VERSION 5.7 ;
  NOWIREEXTENSIONATPIN ON ;
  DIVIDERCHAR "/" ;
  BUSBITCHARS "[]" ;
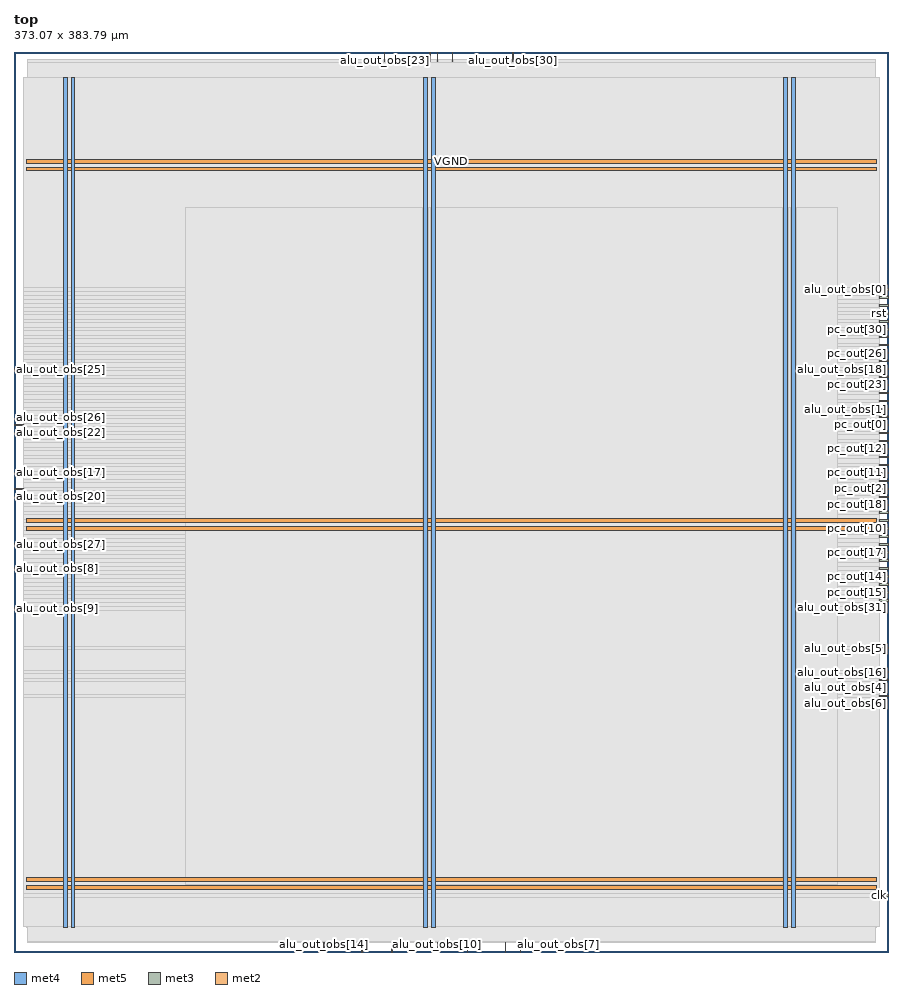
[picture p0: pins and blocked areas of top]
MACRO top
  CLASS BLOCK ;
  FOREIGN top ;
  ORIGIN 0.000 0.000 ;
  SIZE 373.070 BY 383.790 ;
  PIN VGND
    DIRECTION INOUT ;
    USE GROUND ;
    PORT
      LAYER met4 ;
        RECT 24.340 10.640 25.940 372.880 ;
    END
    PORT
      LAYER met4 ;
        RECT 177.940 10.640 179.540 372.880 ;
    END
    PORT
      LAYER met4 ;
        RECT 331.540 10.640 333.140 372.880 ;
    END
    PORT
      LAYER met5 ;
        RECT 5.280 30.030 367.780 31.630 ;
    END
    PORT
      LAYER met5 ;
        RECT 5.280 183.210 367.780 184.810 ;
    END
    PORT
      LAYER met5 ;
        RECT 5.280 336.390 367.780 337.990 ;
    END
  END VGND
  PIN VPWR
    DIRECTION INOUT ;
    USE POWER ;
    PORT
      LAYER met4 ;
        RECT 21.040 10.640 22.640 372.880 ;
    END
    PORT
      LAYER met4 ;
        RECT 174.640 10.640 176.240 372.880 ;
    END
    PORT
      LAYER met4 ;
        RECT 328.240 10.640 329.840 372.880 ;
    END
    PORT
      LAYER met5 ;
        RECT 5.280 26.730 367.780 28.330 ;
    END
    PORT
      LAYER met5 ;
        RECT 5.280 179.910 367.780 181.510 ;
    END
    PORT
      LAYER met5 ;
        RECT 5.280 333.090 367.780 334.690 ;
    END
  END VPWR
  PIN alu_out_obs[0]
    DIRECTION OUTPUT ;
    USE SIGNAL ;
    ANTENNAGATEAREA 0.434700 ;
    ANTENNADIFFAREA 0.775300 ;
    PORT
      LAYER met3 ;
        RECT 369.070 282.240 373.070 282.840 ;
    END
  END alu_out_obs[0]
  PIN alu_out_obs[10]
    DIRECTION OUTPUT ;
    USE SIGNAL ;
    ANTENNAGATEAREA 0.434700 ;
    ANTENNADIFFAREA 0.775300 ;
    PORT
      LAYER met2 ;
        RECT 180.410 0.000 180.690 4.000 ;
    END
  END alu_out_obs[10]
  PIN alu_out_obs[11]
    DIRECTION OUTPUT ;
    USE SIGNAL ;
    ANTENNAGATEAREA 0.434700 ;
    ANTENNADIFFAREA 0.775300 ;
    PORT
      LAYER met2 ;
        RECT 161.090 0.000 161.370 4.000 ;
    END
  END alu_out_obs[11]
  PIN alu_out_obs[12]
    DIRECTION OUTPUT ;
    USE SIGNAL ;
    ANTENNAGATEAREA 0.434700 ;
    ANTENNADIFFAREA 0.775300 ;
    PORT
      LAYER met2 ;
        RECT 177.190 379.790 177.470 383.790 ;
    END
  END alu_out_obs[12]
  PIN alu_out_obs[13]
    DIRECTION OUTPUT ;
    USE SIGNAL ;
    ANTENNAGATEAREA 0.434700 ;
    ANTENNADIFFAREA 0.775300 ;
    PORT
      LAYER met2 ;
        RECT 186.850 379.790 187.130 383.790 ;
    END
  END alu_out_obs[13]
  PIN alu_out_obs[14]
    DIRECTION OUTPUT ;
    USE SIGNAL ;
    ANTENNAGATEAREA 0.434700 ;
    ANTENNADIFFAREA 0.775300 ;
    PORT
      LAYER met2 ;
        RECT 132.110 0.000 132.390 4.000 ;
    END
  END alu_out_obs[14]
  PIN alu_out_obs[15]
    DIRECTION OUTPUT ;
    USE SIGNAL ;
    ANTENNAGATEAREA 0.434700 ;
    ANTENNADIFFAREA 0.775300 ;
    PORT
      LAYER met2 ;
        RECT 215.830 0.000 216.110 4.000 ;
    END
  END alu_out_obs[15]
  PIN alu_out_obs[16]
    DIRECTION OUTPUT ;
    USE SIGNAL ;
    ANTENNAGATEAREA 0.434700 ;
    ANTENNADIFFAREA 0.775300 ;
    PORT
      LAYER met3 ;
        RECT 369.070 119.040 373.070 119.640 ;
    END
  END alu_out_obs[16]
  PIN alu_out_obs[17]
    DIRECTION OUTPUT ;
    USE SIGNAL ;
    ANTENNAGATEAREA 0.434700 ;
    ANTENNADIFFAREA 0.775300 ;
    PORT
      LAYER met3 ;
        RECT 0.000 204.040 4.000 204.640 ;
    END
  END alu_out_obs[17]
  PIN alu_out_obs[18]
    DIRECTION OUTPUT ;
    USE SIGNAL ;
    ANTENNAGATEAREA 0.434700 ;
    ANTENNADIFFAREA 0.775300 ;
    PORT
      LAYER met3 ;
        RECT 369.070 248.240 373.070 248.840 ;
    END
  END alu_out_obs[18]
  PIN alu_out_obs[19]
    DIRECTION OUTPUT ;
    USE SIGNAL ;
    ANTENNAGATEAREA 0.434700 ;
    ANTENNADIFFAREA 0.775300 ;
    PORT
      LAYER met2 ;
        RECT 180.410 379.790 180.690 383.790 ;
    END
  END alu_out_obs[19]
  PIN alu_out_obs[1]
    DIRECTION OUTPUT ;
    USE SIGNAL ;
    ANTENNAGATEAREA 0.434700 ;
    ANTENNADIFFAREA 0.775300 ;
    PORT
      LAYER met3 ;
        RECT 369.070 231.240 373.070 231.840 ;
    END
  END alu_out_obs[1]
  PIN alu_out_obs[20]
    DIRECTION OUTPUT ;
    USE SIGNAL ;
    ANTENNAGATEAREA 0.434700 ;
    ANTENNADIFFAREA 0.775300 ;
    PORT
      LAYER met3 ;
        RECT 0.000 193.840 4.000 194.440 ;
    END
  END alu_out_obs[20]
  PIN alu_out_obs[21]
    DIRECTION OUTPUT ;
    USE SIGNAL ;
    ANTENNAGATEAREA 0.434700 ;
    ANTENNADIFFAREA 0.775300 ;
    PORT
      LAYER met3 ;
        RECT 0.000 197.240 4.000 197.840 ;
    END
  END alu_out_obs[21]
  PIN alu_out_obs[22]
    DIRECTION OUTPUT ;
    USE SIGNAL ;
    ANTENNAGATEAREA 0.434700 ;
    ANTENNADIFFAREA 0.775300 ;
    PORT
      LAYER met3 ;
        RECT 0.000 221.040 4.000 221.640 ;
    END
  END alu_out_obs[22]
  PIN alu_out_obs[23]
    DIRECTION OUTPUT ;
    USE SIGNAL ;
    ANTENNAGATEAREA 0.434700 ;
    ANTENNADIFFAREA 0.775300 ;
    PORT
      LAYER met2 ;
        RECT 157.870 379.790 158.150 383.790 ;
    END
  END alu_out_obs[23]
  PIN alu_out_obs[24]
    DIRECTION OUTPUT ;
    USE SIGNAL ;
    ANTENNAGATEAREA 0.434700 ;
    ANTENNADIFFAREA 0.775300 ;
    PORT
      LAYER met2 ;
        RECT 193.290 0.000 193.570 4.000 ;
    END
  END alu_out_obs[24]
  PIN alu_out_obs[25]
    DIRECTION OUTPUT ;
    USE SIGNAL ;
    ANTENNAGATEAREA 0.434700 ;
    ANTENNADIFFAREA 0.775300 ;
    PORT
      LAYER met3 ;
        RECT 0.000 248.240 4.000 248.840 ;
    END
  END alu_out_obs[25]
  PIN alu_out_obs[26]
    DIRECTION OUTPUT ;
    USE SIGNAL ;
    ANTENNAGATEAREA 0.434700 ;
    ANTENNADIFFAREA 0.775300 ;
    PORT
      LAYER met3 ;
        RECT 0.000 224.440 4.000 225.040 ;
    END
  END alu_out_obs[26]
  PIN alu_out_obs[27]
    DIRECTION OUTPUT ;
    USE SIGNAL ;
    ANTENNAGATEAREA 0.434700 ;
    ANTENNADIFFAREA 0.775300 ;
    PORT
      LAYER met3 ;
        RECT 0.000 173.440 4.000 174.040 ;
    END
  END alu_out_obs[27]
  PIN alu_out_obs[28]
    DIRECTION OUTPUT ;
    USE SIGNAL ;
    ANTENNAGATEAREA 0.434700 ;
    ANTENNADIFFAREA 0.775300 ;
    PORT
      LAYER met2 ;
        RECT 148.210 0.000 148.490 4.000 ;
    END
  END alu_out_obs[28]
  PIN alu_out_obs[29]
    DIRECTION OUTPUT ;
    USE SIGNAL ;
    ANTENNAGATEAREA 0.434700 ;
    ANTENNADIFFAREA 0.775300 ;
    PORT
      LAYER met2 ;
        RECT 209.390 0.000 209.670 4.000 ;
    END
  END alu_out_obs[29]
  PIN alu_out_obs[2]
    DIRECTION OUTPUT ;
    USE SIGNAL ;
    ANTENNAGATEAREA 0.434700 ;
    ANTENNADIFFAREA 0.775300 ;
    PORT
      LAYER met3 ;
        RECT 369.070 251.640 373.070 252.240 ;
    END
  END alu_out_obs[2]
  PIN alu_out_obs[30]
    DIRECTION OUTPUT ;
    USE SIGNAL ;
    ANTENNAGATEAREA 0.434700 ;
    ANTENNADIFFAREA 0.775300 ;
    PORT
      LAYER met2 ;
        RECT 212.610 379.790 212.890 383.790 ;
    END
  END alu_out_obs[30]
  PIN alu_out_obs[31]
    DIRECTION OUTPUT ;
    USE SIGNAL ;
    ANTENNAGATEAREA 0.434700 ;
    ANTENNADIFFAREA 0.775300 ;
    PORT
      LAYER met3 ;
        RECT 369.070 149.640 373.070 150.240 ;
    END
  END alu_out_obs[31]
  PIN alu_out_obs[3]
    DIRECTION OUTPUT ;
    USE SIGNAL ;
    ANTENNAGATEAREA 0.434700 ;
    ANTENNADIFFAREA 0.775300 ;
    PORT
      LAYER met3 ;
        RECT 369.070 258.440 373.070 259.040 ;
    END
  END alu_out_obs[3]
  PIN alu_out_obs[4]
    DIRECTION OUTPUT ;
    USE SIGNAL ;
    ANTENNAGATEAREA 0.434700 ;
    ANTENNADIFFAREA 0.775300 ;
    PORT
      LAYER met3 ;
        RECT 369.070 115.640 373.070 116.240 ;
    END
  END alu_out_obs[4]
  PIN alu_out_obs[5]
    DIRECTION OUTPUT ;
    USE SIGNAL ;
    ANTENNAGATEAREA 0.434700 ;
    ANTENNADIFFAREA 0.775300 ;
    PORT
      LAYER met3 ;
        RECT 369.070 129.240 373.070 129.840 ;
    END
  END alu_out_obs[5]
  PIN alu_out_obs[6]
    DIRECTION OUTPUT ;
    USE SIGNAL ;
    ANTENNAGATEAREA 0.434700 ;
    ANTENNADIFFAREA 0.775300 ;
    PORT
      LAYER met3 ;
        RECT 369.070 108.840 373.070 109.440 ;
    END
  END alu_out_obs[6]
  PIN alu_out_obs[7]
    DIRECTION OUTPUT ;
    USE SIGNAL ;
    ANTENNAGATEAREA 0.434700 ;
    ANTENNADIFFAREA 0.775300 ;
    PORT
      LAYER met2 ;
        RECT 231.930 0.000 232.210 4.000 ;
    END
  END alu_out_obs[7]
  PIN alu_out_obs[8]
    DIRECTION OUTPUT ;
    USE SIGNAL ;
    ANTENNAGATEAREA 0.434700 ;
    ANTENNADIFFAREA 0.775300 ;
    PORT
      LAYER met3 ;
        RECT 0.000 163.240 4.000 163.840 ;
    END
  END alu_out_obs[8]
  PIN alu_out_obs[9]
    DIRECTION OUTPUT ;
    USE SIGNAL ;
    ANTENNAGATEAREA 0.434700 ;
    ANTENNADIFFAREA 0.775300 ;
    PORT
      LAYER met3 ;
        RECT 0.000 146.240 4.000 146.840 ;
    END
  END alu_out_obs[9]
  PIN clk
    DIRECTION INPUT ;
    USE SIGNAL ;
    ANTENNAGATEAREA 1.286700 ;
    ANTENNADIFFAREA 0.434700 ;
    PORT
      LAYER met3 ;
        RECT 369.070 23.840 373.070 24.440 ;
    END
  END clk
  PIN pc_out[0]
    DIRECTION OUTPUT ;
    USE SIGNAL ;
    ANTENNAGATEAREA 0.434700 ;
    ANTENNADIFFAREA 0.775300 ;
    PORT
      LAYER met3 ;
        RECT 369.070 227.840 373.070 228.440 ;
    END
  END pc_out[0]
  PIN pc_out[10]
    DIRECTION OUTPUT ;
    USE SIGNAL ;
    ANTENNAGATEAREA 0.434700 ;
    ANTENNADIFFAREA 0.775300 ;
    PORT
      LAYER met3 ;
        RECT 369.070 180.240 373.070 180.840 ;
    END
  END pc_out[10]
  PIN pc_out[11]
    DIRECTION OUTPUT ;
    USE SIGNAL ;
    ANTENNAGATEAREA 0.434700 ;
    ANTENNADIFFAREA 0.775300 ;
    PORT
      LAYER met3 ;
        RECT 369.070 204.040 373.070 204.640 ;
    END
  END pc_out[11]
  PIN pc_out[12]
    DIRECTION OUTPUT ;
    USE SIGNAL ;
    ANTENNAGATEAREA 0.434700 ;
    ANTENNADIFFAREA 0.775300 ;
    PORT
      LAYER met3 ;
        RECT 369.070 214.240 373.070 214.840 ;
    END
  END pc_out[12]
  PIN pc_out[13]
    DIRECTION OUTPUT ;
    USE SIGNAL ;
    ANTENNAGATEAREA 0.434700 ;
    ANTENNADIFFAREA 0.775300 ;
    PORT
      LAYER met3 ;
        RECT 369.070 210.840 373.070 211.440 ;
    END
  END pc_out[13]
  PIN pc_out[14]
    DIRECTION OUTPUT ;
    USE SIGNAL ;
    ANTENNAGATEAREA 0.434700 ;
    ANTENNADIFFAREA 0.775300 ;
    PORT
      LAYER met3 ;
        RECT 369.070 159.840 373.070 160.440 ;
    END
  END pc_out[14]
  PIN pc_out[15]
    DIRECTION OUTPUT ;
    USE SIGNAL ;
    ANTENNAGATEAREA 0.434700 ;
    ANTENNADIFFAREA 0.775300 ;
    PORT
      LAYER met3 ;
        RECT 369.070 153.040 373.070 153.640 ;
    END
  END pc_out[15]
  PIN pc_out[16]
    DIRECTION OUTPUT ;
    USE SIGNAL ;
    ANTENNAGATEAREA 0.434700 ;
    ANTENNADIFFAREA 0.775300 ;
    PORT
      LAYER met3 ;
        RECT 369.070 207.440 373.070 208.040 ;
    END
  END pc_out[16]
  PIN pc_out[17]
    DIRECTION OUTPUT ;
    USE SIGNAL ;
    ANTENNAGATEAREA 0.434700 ;
    ANTENNADIFFAREA 0.775300 ;
    PORT
      LAYER met3 ;
        RECT 369.070 170.040 373.070 170.640 ;
    END
  END pc_out[17]
  PIN pc_out[18]
    DIRECTION OUTPUT ;
    USE SIGNAL ;
    ANTENNAGATEAREA 0.434700 ;
    ANTENNADIFFAREA 0.775300 ;
    PORT
      LAYER met3 ;
        RECT 369.070 190.440 373.070 191.040 ;
    END
  END pc_out[18]
  PIN pc_out[19]
    DIRECTION OUTPUT ;
    USE SIGNAL ;
    ANTENNAGATEAREA 0.434700 ;
    ANTENNADIFFAREA 0.775300 ;
    PORT
      LAYER met3 ;
        RECT 369.070 200.640 373.070 201.240 ;
    END
  END pc_out[19]
  PIN pc_out[1]
    DIRECTION OUTPUT ;
    USE SIGNAL ;
    ANTENNAGATEAREA 0.434700 ;
    ANTENNADIFFAREA 0.775300 ;
    PORT
      LAYER met3 ;
        RECT 369.070 217.640 373.070 218.240 ;
    END
  END pc_out[1]
  PIN pc_out[20]
    DIRECTION OUTPUT ;
    USE SIGNAL ;
    ANTENNAGATEAREA 0.434700 ;
    ANTENNADIFFAREA 0.775300 ;
    PORT
      LAYER met3 ;
        RECT 369.070 224.440 373.070 225.040 ;
    END
  END pc_out[20]
  PIN pc_out[21]
    DIRECTION OUTPUT ;
    USE SIGNAL ;
    ANTENNAGATEAREA 0.434700 ;
    ANTENNADIFFAREA 0.775300 ;
    PORT
      LAYER met3 ;
        RECT 369.070 234.640 373.070 235.240 ;
    END
  END pc_out[21]
  PIN pc_out[22]
    DIRECTION OUTPUT ;
    USE SIGNAL ;
    ANTENNAGATEAREA 0.434700 ;
    ANTENNADIFFAREA 0.775300 ;
    PORT
      LAYER met3 ;
        RECT 369.070 221.040 373.070 221.640 ;
    END
  END pc_out[22]
  PIN pc_out[23]
    DIRECTION OUTPUT ;
    USE SIGNAL ;
    ANTENNAGATEAREA 0.434700 ;
    ANTENNADIFFAREA 0.775300 ;
    PORT
      LAYER met3 ;
        RECT 369.070 244.840 373.070 245.440 ;
    END
  END pc_out[23]
  PIN pc_out[24]
    DIRECTION OUTPUT ;
    USE SIGNAL ;
    ANTENNAGATEAREA 0.434700 ;
    ANTENNADIFFAREA 0.775300 ;
    PORT
      LAYER met3 ;
        RECT 369.070 238.040 373.070 238.640 ;
    END
  END pc_out[24]
  PIN pc_out[25]
    DIRECTION OUTPUT ;
    USE SIGNAL ;
    ANTENNAGATEAREA 0.434700 ;
    ANTENNADIFFAREA 0.775300 ;
    PORT
      LAYER met3 ;
        RECT 369.070 241.440 373.070 242.040 ;
    END
  END pc_out[25]
  PIN pc_out[26]
    DIRECTION OUTPUT ;
    USE SIGNAL ;
    ANTENNAGATEAREA 0.434700 ;
    ANTENNADIFFAREA 0.775300 ;
    PORT
      LAYER met3 ;
        RECT 369.070 255.040 373.070 255.640 ;
    END
  END pc_out[26]
  PIN pc_out[27]
    DIRECTION OUTPUT ;
    USE SIGNAL ;
    ANTENNAGATEAREA 0.434700 ;
    ANTENNADIFFAREA 0.775300 ;
    PORT
      LAYER met3 ;
        RECT 369.070 278.840 373.070 279.440 ;
    END
  END pc_out[27]
  PIN pc_out[28]
    DIRECTION OUTPUT ;
    USE SIGNAL ;
    ANTENNAGATEAREA 0.434700 ;
    ANTENNADIFFAREA 0.775300 ;
    PORT
      LAYER met3 ;
        RECT 369.070 261.840 373.070 262.440 ;
    END
  END pc_out[28]
  PIN pc_out[29]
    DIRECTION OUTPUT ;
    USE SIGNAL ;
    ANTENNAGATEAREA 0.434700 ;
    ANTENNADIFFAREA 0.775300 ;
    PORT
      LAYER met3 ;
        RECT 369.070 268.640 373.070 269.240 ;
    END
  END pc_out[29]
  PIN pc_out[2]
    DIRECTION OUTPUT ;
    USE SIGNAL ;
    ANTENNAGATEAREA 0.434700 ;
    ANTENNADIFFAREA 0.775300 ;
    PORT
      LAYER met3 ;
        RECT 369.070 197.240 373.070 197.840 ;
    END
  END pc_out[2]
  PIN pc_out[30]
    DIRECTION OUTPUT ;
    USE SIGNAL ;
    ANTENNAGATEAREA 0.434700 ;
    ANTENNADIFFAREA 0.775300 ;
    PORT
      LAYER met3 ;
        RECT 369.070 265.240 373.070 265.840 ;
    END
  END pc_out[30]
  PIN pc_out[31]
    DIRECTION OUTPUT ;
    USE SIGNAL ;
    ANTENNAGATEAREA 0.434700 ;
    ANTENNADIFFAREA 0.775300 ;
    PORT
      LAYER met3 ;
        RECT 369.070 275.440 373.070 276.040 ;
    END
  END pc_out[31]
  PIN pc_out[3]
    DIRECTION OUTPUT ;
    USE SIGNAL ;
    ANTENNAGATEAREA 0.434700 ;
    ANTENNADIFFAREA 0.775300 ;
    PORT
      LAYER met3 ;
        RECT 369.070 176.840 373.070 177.440 ;
    END
  END pc_out[3]
  PIN pc_out[4]
    DIRECTION OUTPUT ;
    USE SIGNAL ;
    ANTENNAGATEAREA 0.434700 ;
    ANTENNADIFFAREA 0.775300 ;
    PORT
      LAYER met3 ;
        RECT 369.070 183.640 373.070 184.240 ;
    END
  END pc_out[4]
  PIN pc_out[5]
    DIRECTION OUTPUT ;
    USE SIGNAL ;
    ANTENNAGATEAREA 0.434700 ;
    ANTENNADIFFAREA 0.775300 ;
    PORT
      LAYER met3 ;
        RECT 369.070 187.040 373.070 187.640 ;
    END
  END pc_out[5]
  PIN pc_out[6]
    DIRECTION OUTPUT ;
    USE SIGNAL ;
    ANTENNAGATEAREA 0.434700 ;
    ANTENNADIFFAREA 0.775300 ;
    PORT
      LAYER met3 ;
        RECT 369.070 173.440 373.070 174.040 ;
    END
  END pc_out[6]
  PIN pc_out[7]
    DIRECTION OUTPUT ;
    USE SIGNAL ;
    ANTENNAGATEAREA 0.434700 ;
    ANTENNADIFFAREA 0.775300 ;
    PORT
      LAYER met3 ;
        RECT 369.070 163.240 373.070 163.840 ;
    END
  END pc_out[7]
  PIN pc_out[8]
    DIRECTION OUTPUT ;
    USE SIGNAL ;
    ANTENNAGATEAREA 0.434700 ;
    ANTENNADIFFAREA 0.775300 ;
    PORT
      LAYER met3 ;
        RECT 369.070 166.640 373.070 167.240 ;
    END
  END pc_out[8]
  PIN pc_out[9]
    DIRECTION OUTPUT ;
    USE SIGNAL ;
    ANTENNAGATEAREA 0.434700 ;
    ANTENNADIFFAREA 0.775300 ;
    PORT
      LAYER met3 ;
        RECT 369.070 193.840 373.070 194.440 ;
    END
  END pc_out[9]
  PIN reg_write_obs
    DIRECTION OUTPUT ;
    USE SIGNAL ;
    ANTENNAGATEAREA 0.434700 ;
    ANTENNADIFFAREA 0.775300 ;
    PORT
      LAYER met3 ;
        RECT 369.070 156.440 373.070 157.040 ;
    END
  END reg_write_obs
  PIN rst
    DIRECTION INPUT ;
    USE SIGNAL ;
    ANTENNAGATEAREA 0.560700 ;
    ANTENNADIFFAREA 0.434700 ;
    PORT
      LAYER met3 ;
        RECT 369.070 272.040 373.070 272.640 ;
    END
  END rst
  OBS
      LAYER nwell ;
        RECT 5.330 10.795 367.730 372.830 ;
      LAYER li1 ;
        RECT 5.520 10.795 367.540 372.725 ;
      LAYER met1 ;
        RECT 5.520 10.640 367.840 372.880 ;
      LAYER met2 ;
        RECT 5.610 379.510 157.590 380.530 ;
        RECT 158.430 379.510 176.910 380.530 ;
        RECT 177.750 379.510 180.130 380.530 ;
        RECT 180.970 379.510 186.570 380.530 ;
        RECT 187.410 379.510 212.330 380.530 ;
        RECT 213.170 379.510 367.450 380.530 ;
        RECT 5.610 4.280 367.450 379.510 ;
        RECT 5.610 4.000 131.830 4.280 ;
        RECT 132.670 4.000 147.930 4.280 ;
        RECT 148.770 4.000 160.810 4.280 ;
        RECT 161.650 4.000 180.130 4.280 ;
        RECT 180.970 4.000 193.010 4.280 ;
        RECT 193.850 4.000 209.110 4.280 ;
        RECT 209.950 4.000 215.550 4.280 ;
        RECT 216.390 4.000 231.650 4.280 ;
        RECT 232.490 4.000 367.450 4.280 ;
      LAYER met3 ;
        RECT 4.000 283.240 369.070 372.805 ;
        RECT 4.000 281.840 368.670 283.240 ;
        RECT 4.000 279.840 369.070 281.840 ;
        RECT 4.000 278.440 368.670 279.840 ;
        RECT 4.000 276.440 369.070 278.440 ;
        RECT 4.000 275.040 368.670 276.440 ;
        RECT 4.000 273.040 369.070 275.040 ;
        RECT 4.000 271.640 368.670 273.040 ;
        RECT 4.000 269.640 369.070 271.640 ;
        RECT 4.000 268.240 368.670 269.640 ;
        RECT 4.000 266.240 369.070 268.240 ;
        RECT 4.000 264.840 368.670 266.240 ;
        RECT 4.000 262.840 369.070 264.840 ;
        RECT 4.000 261.440 368.670 262.840 ;
        RECT 4.000 259.440 369.070 261.440 ;
        RECT 4.000 258.040 368.670 259.440 ;
        RECT 4.000 256.040 369.070 258.040 ;
        RECT 4.000 254.640 368.670 256.040 ;
        RECT 4.000 252.640 369.070 254.640 ;
        RECT 4.000 251.240 368.670 252.640 ;
        RECT 4.000 249.240 369.070 251.240 ;
        RECT 4.400 247.840 368.670 249.240 ;
        RECT 4.000 245.840 369.070 247.840 ;
        RECT 4.000 244.440 368.670 245.840 ;
        RECT 4.000 242.440 369.070 244.440 ;
        RECT 4.000 241.040 368.670 242.440 ;
        RECT 4.000 239.040 369.070 241.040 ;
        RECT 4.000 237.640 368.670 239.040 ;
        RECT 4.000 235.640 369.070 237.640 ;
        RECT 4.000 234.240 368.670 235.640 ;
        RECT 4.000 232.240 369.070 234.240 ;
        RECT 4.000 230.840 368.670 232.240 ;
        RECT 4.000 228.840 369.070 230.840 ;
        RECT 4.000 227.440 368.670 228.840 ;
        RECT 4.000 225.440 369.070 227.440 ;
        RECT 4.400 224.040 368.670 225.440 ;
        RECT 4.000 222.040 369.070 224.040 ;
        RECT 4.400 220.640 368.670 222.040 ;
        RECT 4.000 218.640 369.070 220.640 ;
        RECT 4.000 217.240 368.670 218.640 ;
        RECT 4.000 215.240 369.070 217.240 ;
        RECT 4.000 213.840 368.670 215.240 ;
        RECT 4.000 211.840 369.070 213.840 ;
        RECT 4.000 210.440 368.670 211.840 ;
        RECT 4.000 208.440 369.070 210.440 ;
        RECT 4.000 207.040 368.670 208.440 ;
        RECT 4.000 205.040 369.070 207.040 ;
        RECT 4.400 203.640 368.670 205.040 ;
        RECT 4.000 201.640 369.070 203.640 ;
        RECT 4.000 200.240 368.670 201.640 ;
        RECT 4.000 198.240 369.070 200.240 ;
        RECT 4.400 196.840 368.670 198.240 ;
        RECT 4.000 194.840 369.070 196.840 ;
        RECT 4.400 193.440 368.670 194.840 ;
        RECT 4.000 191.440 369.070 193.440 ;
        RECT 4.000 190.040 368.670 191.440 ;
        RECT 4.000 188.040 369.070 190.040 ;
        RECT 4.000 186.640 368.670 188.040 ;
        RECT 4.000 184.640 369.070 186.640 ;
        RECT 4.000 183.240 368.670 184.640 ;
        RECT 4.000 181.240 369.070 183.240 ;
        RECT 4.000 179.840 368.670 181.240 ;
        RECT 4.000 177.840 369.070 179.840 ;
        RECT 4.000 176.440 368.670 177.840 ;
        RECT 4.000 174.440 369.070 176.440 ;
        RECT 4.400 173.040 368.670 174.440 ;
        RECT 4.000 171.040 369.070 173.040 ;
        RECT 4.000 169.640 368.670 171.040 ;
        RECT 4.000 167.640 369.070 169.640 ;
        RECT 4.000 166.240 368.670 167.640 ;
        RECT 4.000 164.240 369.070 166.240 ;
        RECT 4.400 162.840 368.670 164.240 ;
        RECT 4.000 160.840 369.070 162.840 ;
        RECT 4.000 159.440 368.670 160.840 ;
        RECT 4.000 157.440 369.070 159.440 ;
        RECT 4.000 156.040 368.670 157.440 ;
        RECT 4.000 154.040 369.070 156.040 ;
        RECT 4.000 152.640 368.670 154.040 ;
        RECT 4.000 150.640 369.070 152.640 ;
        RECT 4.000 149.240 368.670 150.640 ;
        RECT 4.000 147.240 369.070 149.240 ;
        RECT 4.400 145.840 369.070 147.240 ;
        RECT 4.000 130.240 369.070 145.840 ;
        RECT 4.000 128.840 368.670 130.240 ;
        RECT 4.000 120.040 369.070 128.840 ;
        RECT 4.000 118.640 368.670 120.040 ;
        RECT 4.000 116.640 369.070 118.640 ;
        RECT 4.000 115.240 368.670 116.640 ;
        RECT 4.000 109.840 369.070 115.240 ;
        RECT 4.000 108.440 368.670 109.840 ;
        RECT 4.000 24.840 369.070 108.440 ;
        RECT 4.000 23.440 368.670 24.840 ;
        RECT 4.000 10.715 369.070 23.440 ;
      LAYER met4 ;
        RECT 72.975 28.735 174.240 317.385 ;
        RECT 176.640 28.735 177.540 317.385 ;
        RECT 179.940 28.735 327.840 317.385 ;
        RECT 330.240 28.735 331.140 317.385 ;
        RECT 333.540 28.735 351.145 317.385 ;
  END
END top
END LIBRARY

